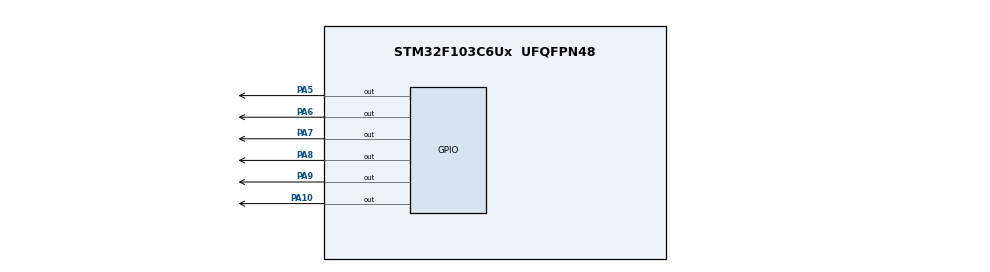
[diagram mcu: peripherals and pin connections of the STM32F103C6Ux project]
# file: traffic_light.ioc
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Mcu.Family=STM32F1
Mcu.Name=STM32F103C6Ux
Mcu.Package=UFQFPN48
NVIC.PriorityGroup=NVIC_PRIORITYGROUP_4
PA10.Signal=GPIO_Output
PA5.Signal=GPIO_Output
PA6.Signal=GPIO_Output
PA7.Signal=GPIO_Output
PA8.Signal=GPIO_Output
PA9.Signal=GPIO_Output
ProjectManager.HeapSize=0x200
ProjectManager.StackSize=0x400
ProjectManager.TargetToolchain=STM32CubeIDE
RCC.APB1Freq_Value=8000000
RCC.APB2Freq_Value=8000000
VP_SYS_VS_ND.Mode=No_Debug
board=custom

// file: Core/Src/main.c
/* USER CODE BEGIN Header */
/**
  ******************************************************************************
  * @file           : main.c
  * @brief          : Main program body - Traffic Light with 7-Segment Display
  ******************************************************************************
  * @attention
  *
  * Copyright (c) 2026 STMicroelectronics.
  * All rights reserved.
  *
  ******************************************************************************
  */
/* USER CODE END Header */
#include "main.h"

void SystemClock_Config(void);
static void MX_GPIO_Init(void);

int main(void)
{

  /* MCU Configuration--------------------------------------------------------*/

  /* Reset of all peripherals, Initializes the Flash interface and the Systick. */
  HAL_Init();

  /* Configure the system clock */
  SystemClock_Config();

  /* Initialize all configured peripherals */
  MX_GPIO_Init();

  /* Infinite loop */
  while (1)
  {

    /* USER CODE BEGIN 3 */
    HAL_GPIO_WritePin(GPIOA, GPIO_PIN_5, GPIO_PIN_SET);    // red north active
    HAL_GPIO_WritePin(GPIOA, GPIO_PIN_6, GPIO_PIN_RESET);
    HAL_GPIO_WritePin(GPIOA, GPIO_PIN_7, GPIO_PIN_RESET);

    HAL_GPIO_WritePin(GPIOA, GPIO_PIN_8, GPIO_PIN_RESET);
    HAL_GPIO_WritePin(GPIOA, GPIO_PIN_9, GPIO_PIN_RESET);
    HAL_GPIO_WritePin(GPIOA, GPIO_PIN_10, GPIO_PIN_SET);

    for (int t = 3; t >= 1; t--)
    {
        HAL_Delay(1000);
    }

    HAL_GPIO_WritePin(GPIOA, GPIO_PIN_5, GPIO_PIN_SET);
    HAL_GPIO_WritePin(GPIOA, GPIO_PIN_6, GPIO_PIN_RESET);
    HAL_GPIO_WritePin(GPIOA, GPIO_PIN_7, GPIO_PIN_RESET);

    HAL_GPIO_WritePin(GPIOA, GPIO_PIN_8, GPIO_PIN_RESET);
    HAL_GPIO_WritePin(GPIOA, GPIO_PIN_9, GPIO_PIN_SET);
    HAL_GPIO_WritePin(GPIOA, GPIO_PIN_10, GPIO_PIN_RESET);

    for (int t = 2; t >= 1; t--)
    {
        HAL_Delay(1000);
    }

    HAL_GPIO_WritePin(GPIOA, GPIO_PIN_5, GPIO_PIN_RESET);  // red west active
    HAL_GPIO_WritePin(GPIOA, GPIO_PIN_6, GPIO_PIN_RESET);
    HAL_GPIO_WritePin(GPIOA, GPIO_PIN_7, GPIO_PIN_SET);

    HAL_GPIO_WritePin(GPIOA, GPIO_PIN_8, GPIO_PIN_SET);
    HAL_GPIO_WritePin(GPIOA, GPIO_PIN_9, GPIO_PIN_RESET);
    HAL_GPIO_WritePin(GPIOA, GPIO_PIN_10, GPIO_PIN_RESET);

    for (int t = 3; t >= 1; t--)
    {
        HAL_Delay(1000);
    }

    HAL_GPIO_WritePin(GPIOA, GPIO_PIN_5, GPIO_PIN_RESET);
    HAL_GPIO_WritePin(GPIOA, GPIO_PIN_6, GPIO_PIN_SET);
    HAL_GPIO_WritePin(GPIOA, GPIO_PIN_7, GPIO_PIN_RESET);

    HAL_GPIO_WritePin(GPIOA, GPIO_PIN_8, GPIO_PIN_SET);
    HAL_GPIO_WritePin(GPIOA, GPIO_PIN_9, GPIO_PIN_RESET);
    HAL_GPIO_WritePin(GPIOA, GPIO_PIN_10, GPIO_PIN_RESET);

    for (int t = 2; t >= 1; t--)
    {
        HAL_Delay(1000);
    }
    /* USER CODE END 3 */
  }
}

void SystemClock_Config(void)
{
  RCC_OscInitTypeDef RCC_OscInitStruct = {0};
  RCC_ClkInitTypeDef RCC_ClkInitStruct = {0};

  RCC_OscInitStruct.OscillatorType = RCC_OSCILLATORTYPE_HSI;
  RCC_OscInitStruct.HSIState = RCC_HSI_ON;
  RCC_OscInitStruct.HSICalibrationValue = RCC_HSICALIBRATION_DEFAULT;
  RCC_OscInitStruct.PLL.PLLState = RCC_PLL_NONE;
  if (HAL_RCC_OscConfig(&RCC_OscInitStruct) != HAL_OK)
  {
    Error_Handler();
  }

  RCC_ClkInitStruct.ClockType = RCC_CLOCKTYPE_HCLK|RCC_CLOCKTYPE_SYSCLK
                              |RCC_CLOCKTYPE_PCLK1|RCC_CLOCKTYPE_PCLK2;
  RCC_ClkInitStruct.SYSCLKSource = RCC_SYSCLKSOURCE_HSI;
  RCC_ClkInitStruct.AHBCLKDivider = RCC_SYSCLK_DIV1;
  RCC_ClkInitStruct.APB1CLKDivider = RCC_HCLK_DIV1;
  RCC_ClkInitStruct.APB2CLKDivider = RCC_HCLK_DIV1;

  if (HAL_RCC_ClockConfig(&RCC_ClkInitStruct, FLASH_LATENCY_0) != HAL_OK)
  {
    Error_Handler();
  }
}

static void MX_GPIO_Init(void)
{
  GPIO_InitTypeDef GPIO_InitStruct = {0};

  /* Cấp clock cho Port A và Port B */
  __HAL_RCC_GPIOA_CLK_ENABLE();
  __HAL_RCC_GPIOB_CLK_ENABLE();

  /* Đặt mức xuất ban đầu */
  HAL_GPIO_WritePin(GPIOA, GPIO_PIN_5|GPIO_PIN_6|GPIO_PIN_7
                          |GPIO_PIN_8|GPIO_PIN_9|GPIO_PIN_10, GPIO_PIN_RESET);
  HAL_GPIO_WritePin(GPIOB, GPIO_PIN_0|GPIO_PIN_1|GPIO_PIN_2|GPIO_PIN_3
                          |GPIO_PIN_4|GPIO_PIN_5|GPIO_PIN_6, GPIO_PIN_SET);

  /* Cấu hình các chân điều khiển đèn giao thông: PA5 -> PA10 */
  GPIO_InitStruct.Pin = GPIO_PIN_5|GPIO_PIN_6|GPIO_PIN_7
                        |GPIO_PIN_8|GPIO_PIN_9|GPIO_PIN_10;
  GPIO_InitStruct.Mode = GPIO_MODE_OUTPUT_PP;
  GPIO_InitStruct.Pull = GPIO_NOPULL;
  GPIO_InitStruct.Speed = GPIO_SPEED_FREQ_LOW;
  HAL_GPIO_Init(GPIOA, &GPIO_InitStruct);

  /* Cấu hình các chân xuất ra LED 7 đoạn: PB0 -> PB6 */
  GPIO_InitStruct.Pin = GPIO_PIN_0|GPIO_PIN_1|GPIO_PIN_2|GPIO_PIN_3
                        |GPIO_PIN_4|GPIO_PIN_5|GPIO_PIN_6;
  GPIO_InitStruct.Mode = GPIO_MODE_OUTPUT_PP;
  GPIO_InitStruct.Pull = GPIO_NOPULL;
  GPIO_InitStruct.Speed = GPIO_SPEED_FREQ_LOW;
  HAL_GPIO_Init(GPIOB, &GPIO_InitStruct);
}

void Error_Handler(void)
{
  __disable_irq();
  while (1)
  {
  }
}
